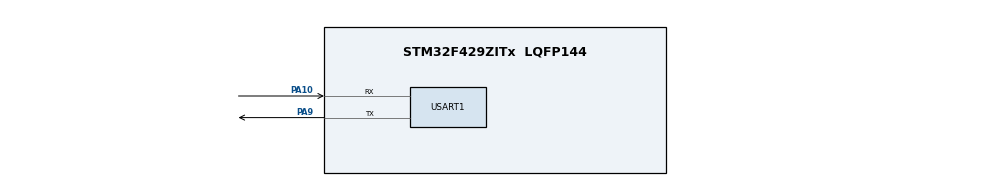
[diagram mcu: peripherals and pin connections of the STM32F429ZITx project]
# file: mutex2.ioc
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FREERTOS.Tasks01=defaultTask,0,128,StartDefaultTask,Default,NULL,Dynamic,NULL,NULL
Mcu.Family=STM32F4
Mcu.Name=STM32F429ZITx
Mcu.Package=LQFP144
NVIC.PriorityGroup=NVIC_PRIORITYGROUP_4
NVIC.TIM1_UP_TIM10_IRQn=true\:15\:0\:false\:false\:true\:false\:false\:true\:true
NVIC.TimeBase=TIM1_UP_TIM10_IRQn
NVIC.TimeBaseIP=TIM1
PA10.Mode=Asynchronous
PA10.Signal=USART1_RX
PA13.Mode=Serial_Wire
PA13.Signal=SYS_JTMS-SWDIO
PA14.Mode=Serial_Wire
PA14.Signal=SYS_JTCK-SWCLK
PA9.Mode=Asynchronous
PA9.Signal=USART1_TX
PH0/OSC_IN.Mode=HSE-External-Oscillator
PH0/OSC_IN.Signal=RCC_OSC_IN
PH1/OSC_OUT.Mode=HSE-External-Oscillator
PH1/OSC_OUT.Signal=RCC_OSC_OUT
ProjectManager.HeapSize=0x200
ProjectManager.StackSize=0x400
ProjectManager.TargetToolchain=STM32CubeIDE
RCC.48MHZClocksFreq_Value=48000000
RCC.AHBFreq_Value=72000000
RCC.APB1CLKDivider=RCC_HCLK_DIV2
RCC.APB1Freq_Value=36000000
RCC.APB1TimFreq_Value=72000000
RCC.APB2Freq_Value=72000000
RCC.APB2TimFreq_Value=72000000
RCC.CortexFreq_Value=72000000
RCC.HCLKFreq_Value=72000000
RCC.HSE_VALUE=8000000
RCC.HSI_VALUE=16000000
RCC.LSE_VALUE=32768
RCC.PLLM=4
RCC.PLLN=72
RCC.PLLQ=3
RCC.PLLSAIN=50
RCC.PLLSourceVirtual=RCC_PLLSOURCE_HSE
RCC.SYSCLKFreq_VALUE=72000000
RCC.SYSCLKSource=RCC_SYSCLKSOURCE_PLLCLK
RCC.VCOOutputFreq_Value=144000000
USART1.VirtualMode=VM_ASYNC
VP_FREERTOS_VS_CMSIS_V1.Mode=CMSIS_V1
VP_SYS_VS_tim1.Mode=TIM1
board=STM32F429I-DISC1

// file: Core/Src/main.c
/* USER CODE BEGIN Header */
/**
  ******************************************************************************
  * @file           : main.c
  * @brief          : Main program body
  ******************************************************************************
  * @attention
  *
  * Copyright (c) 2025 STMicroelectronics.
  * All rights reserved.
  *
  * This software is licensed under terms that can be found in the LICENSE file
  * in the root directory of this software component.
  * If no LICENSE file comes with this software, it is provided AS-IS.
  *
  ******************************************************************************
  */
/* USER CODE END Header */
#include "main.h"
//#include "cmsis_os.h"

/* USER CODE BEGIN Includes */
#include "FreeRTOS.h"
#include "task.h"
//#include "timers.h"
#include "queue.h"
#include "semphr.h"
//#include "event_groups.h"

#include "string.h"
#include "stdio.h"

/* USER CODE END Includes */

UART_HandleTypeDef huart1;

void SystemClock_Config(void);
static void MX_GPIO_Init(void);
static void MX_USART1_UART_Init(void);

/* USER CODE BEGIN 0 */
SemaphoreHandle_t SimpleMutex;
SemaphoreHandle_t BinSemaphore;

TaskHandle_t HPT_Handler;
TaskHandle_t MPT_Handler;
TaskHandle_t LPT_Handler;

void HPT_Task (void *argument);
void MPT_Task (void *argument);
void LPT_Task (void *argument);

void Send_Uart (uint8_t *str)
{
	xSemaphoreTake(SimpleMutex, portMAX_DELAY);
	HAL_Delay(5000);
	HAL_UART_Transmit(&huart1, (uint8_t*)str, strlen (str), HAL_MAX_DELAY);
	xSemaphoreGive(SimpleMutex);
}
/* USER CODE END 0 */

int main(void)
{

  /* MCU Configuration--------------------------------------------------------*/

  /* Reset of all peripherals, Initializes the Flash interface and the Systick. */
  HAL_Init();

  /* Configure the system clock */
  SystemClock_Config();

  /* Initialize all configured peripherals */
  MX_GPIO_Init();
  MX_USART1_UART_Init();
  /* USER CODE BEGIN 2 */

  SimpleMutex = xSemaphoreCreateMutex();

  if(SimpleMutex != NULL)
  {
	 HAL_UART_Transmit(&huart1, (uint8_t*)"Mutex Created\n\n", 15, 1000);

  }

  BinSemaphore = xSemaphoreCreateBinary();

  if(BinSemaphore != NULL)
  {
	 HAL_UART_Transmit(&huart1, (uint8_t*)"Binary Sem. Created\n\n", 25, 1000);

  }

  xSemaphoreGive(BinSemaphore);

  ///create tasks

  xTaskCreate(HPT_Task, "HPT", 128, NULL, 3, &HPT_Handler);
  xTaskCreate(MPT_Task, "MPT", 128, NULL, 2, &MPT_Handler);
  xTaskCreate(LPT_Task, "LPT", 128, NULL, 1, &LPT_Handler);

  vTaskStartScheduler();

  /* USER CODE END 2 */

  /* Create the thread(s) */
  /* definition and creation of defaultTask */

  /* Start scheduler */

  /* We should never get here as control is now taken by the scheduler */

  /* Infinite loop */
  while (1)
  {

  }
}

void SystemClock_Config(void)
{
  RCC_OscInitTypeDef RCC_OscInitStruct = {0};
  RCC_ClkInitTypeDef RCC_ClkInitStruct = {0};

  /** Configure the main internal regulator output voltage
  */
  __HAL_RCC_PWR_CLK_ENABLE();
  __HAL_PWR_VOLTAGESCALING_CONFIG(PWR_REGULATOR_VOLTAGE_SCALE1);

  /** Initializes the RCC Oscillators according to the specified parameters
  * in the RCC_OscInitTypeDef structure.
  */
  RCC_OscInitStruct.OscillatorType = RCC_OSCILLATORTYPE_HSE;
  RCC_OscInitStruct.HSEState = RCC_HSE_ON;
  RCC_OscInitStruct.PLL.PLLState = RCC_PLL_ON;
  RCC_OscInitStruct.PLL.PLLSource = RCC_PLLSOURCE_HSE;
  RCC_OscInitStruct.PLL.PLLM = 4;
  RCC_OscInitStruct.PLL.PLLN = 180;
  RCC_OscInitStruct.PLL.PLLP = RCC_PLLP_DIV2;
  RCC_OscInitStruct.PLL.PLLQ = 3;
  if (HAL_RCC_OscConfig(&RCC_OscInitStruct) != HAL_OK)
  {
    Error_Handler();
  }

  /** Activate the Over-Drive mode
  */
  if (HAL_PWREx_EnableOverDrive() != HAL_OK)
  {
    Error_Handler();
  }

  /** Initializes the CPU, AHB and APB buses clocks
  */
  RCC_ClkInitStruct.ClockType = RCC_CLOCKTYPE_HCLK|RCC_CLOCKTYPE_SYSCLK
                              |RCC_CLOCKTYPE_PCLK1|RCC_CLOCKTYPE_PCLK2;
  RCC_ClkInitStruct.SYSCLKSource = RCC_SYSCLKSOURCE_PLLCLK;
  RCC_ClkInitStruct.AHBCLKDivider = RCC_SYSCLK_DIV1;
  RCC_ClkInitStruct.APB1CLKDivider = RCC_HCLK_DIV4;
  RCC_ClkInitStruct.APB2CLKDivider = RCC_HCLK_DIV2;

  if (HAL_RCC_ClockConfig(&RCC_ClkInitStruct, FLASH_LATENCY_5) != HAL_OK)
  {
    Error_Handler();
  }
}

static void MX_USART1_UART_Init(void)
{

  huart1.Instance = USART1;
  huart1.Init.BaudRate = 115200;
  huart1.Init.WordLength = UART_WORDLENGTH_8B;
  huart1.Init.StopBits = UART_STOPBITS_1;
  huart1.Init.Parity = UART_PARITY_NONE;
  huart1.Init.Mode = UART_MODE_TX_RX;
  huart1.Init.HwFlowCtl = UART_HWCONTROL_NONE;
  huart1.Init.OverSampling = UART_OVERSAMPLING_16;
  if (HAL_UART_Init(&huart1) != HAL_OK)
  {
    Error_Handler();
  }

}

static void MX_GPIO_Init(void)
{

  /* GPIO Ports Clock Enable */
  __HAL_RCC_GPIOH_CLK_ENABLE();
  __HAL_RCC_GPIOA_CLK_ENABLE();

}

/* USER CODE BEGIN 4 */
void HPT_Task(void *argument)
{
	char *strtosend = "IN HPT ======================\n";

	while(1)
	{
		char *str =" Entered HPT and about to take Mutex\n";
		HAL_UART_Transmit(&huart1, (uint8_t *)str, strlen(str), HAL_MAX_DELAY);

		Send_Uart(strtosend);

		char *str2 =" leaving HPT \n\n";
		HAL_UART_Transmit(&huart1, (uint8_t *)str2, strlen(str2), HAL_MAX_DELAY);

		vTaskDelay(750);

	}
}

void MPT_Task(void *argument)
{

	while(1)
	{
		char *str = "IN MPT ======================\n";
		HAL_UART_Transmit(&huart1, (uint8_t *)str, strlen(str), HAL_MAX_DELAY);

		vTaskDelay(2000);

	}
}

void LPT_Task(void *argument)
{
	char *strtosend = "IN LPT ======================\n";

	while(1)
	{
		char *str =" Entered LPT and about to take Mutex\n";
		HAL_UART_Transmit(&huart1, (uint8_t *)str, strlen(str), HAL_MAX_DELAY);

		Send_Uart(strtosend);

		char *str2 =" leaving LPT \n\n";
		HAL_UART_Transmit(&huart1, (uint8_t *)str2, strlen(str2), HAL_MAX_DELAY);

		vTaskDelay(1000);

	}
}

/* USER CODE END 4 */

void HAL_TIM_PeriodElapsedCallback(TIM_HandleTypeDef *htim)
{
  if (htim->Instance == TIM1) {
    HAL_IncTick();
  }
}

void Error_Handler(void)
{
  __disable_irq();
  while (1)
  {
  }
}
